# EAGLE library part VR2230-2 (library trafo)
TRANSFORMER 1 primary winding, 2 secondary windings, mounting holes BLOCK

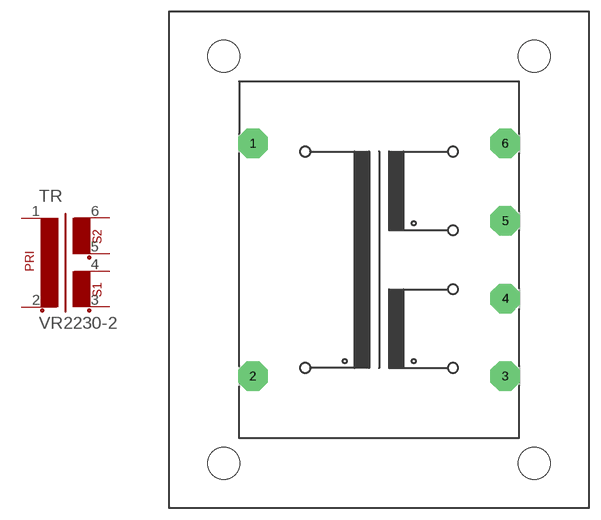
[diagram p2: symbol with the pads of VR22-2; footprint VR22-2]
Designator prefix TR

## VR2230-2  [VR22-2]
1  1  pas
2  2  pas
3  3  pas
4  4  pas
5  5  pas
6  6  pas

## Footprint VR22-2 (pad centres in mm)
TRANSFORMER 1 primary winding, 2 secondary windings, mounting holes
drill 1.397 pad 3.81 octagon: 1 -16.256,15.011; 2 -16.256,-15.011; 3 16.256,-15.011; 4 16.256,-5.004; 5 16.256,5.004; 6 16.256,15.011
hole 4.115 at -19.99,-26.264
hole 4.115 at -19.99,26.264
hole 4.115 at 19.99,-26.264
hole 4.115 at 19.99,26.264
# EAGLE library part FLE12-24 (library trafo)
TRANSFORMER 2 primary winding, temp. protection fuse, 2 secondary windings, mounting holes BLOCK

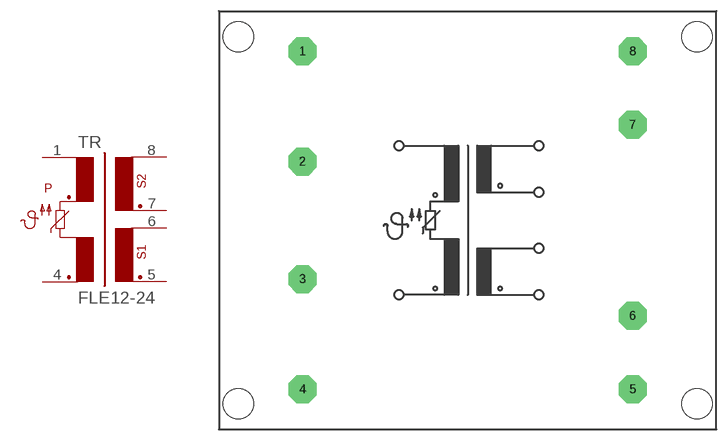
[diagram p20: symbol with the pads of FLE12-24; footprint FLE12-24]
Designator prefix TR

## FLE12-24  [FLE12-24]
1  1  pas
4  4  pas
5  5  pas
6  6  pas
7  7  pas
8  8  pas

## Footprint FLE12-24 (pad centres in mm)
TRANSFORMER 2 primary winding, 2 secondary windings, temp. protection fuse, mounting holes
drill 1.194 pad 3.81 octagon: 1 -22.504,23.012; 2 -22.504,8.001; 3 -22.504,-8.001; 4 -22.504,-23.012; 5 22.504,-23.012; 6 22.504,-13.005; 7 22.504,13.005; 8 22.504,23.012
hole 4.115 at -31.267,24.994
hole 4.115 at 31.267,24.994
hole 4.115 at 31.267,-24.994
hole 4.115 at -31.267,-24.994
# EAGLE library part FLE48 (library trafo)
TRANSFORMER 2 primary winding, temp. protection fuse, 2 secondary windings, mounting holes BLOCK

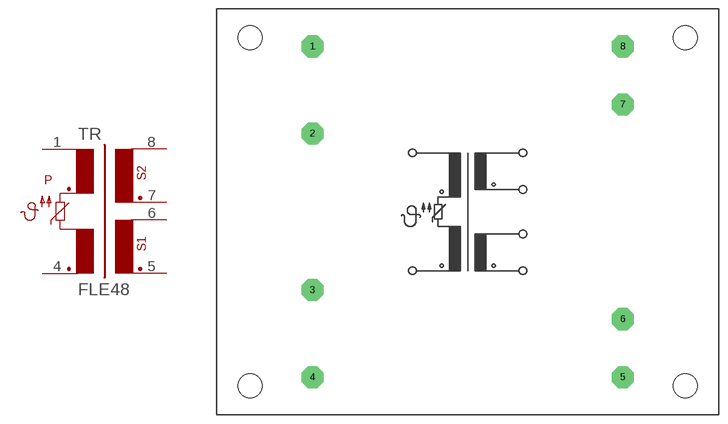
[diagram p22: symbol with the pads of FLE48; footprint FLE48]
Designator prefix TR

## FLE48  [FLE48]
1  1  pas
4  4  pas
5  5  pas
6  6  pas
7  7  pas
8  8  pas

## Footprint FLE48 (pad centres in mm)
TRANSFORMER 2 primary winding, 2 secondary windings, temp. protection fuse, mounting holes
drill 1.397 pad 3.81 octagon: 1 -26.746,28.499; 2 -26.746,13.487; 3 -26.746,-13.487; 4 -26.746,-28.499; 5 26.746,-28.499; 6 26.746,-18.491; 7 26.746,18.491; 8 26.746,28.499
hole 4.115 at -37.49,-29.997
hole 4.115 at -37.49,29.997
hole 4.115 at 37.49,29.997
hole 4.115 at 37.49,-29.997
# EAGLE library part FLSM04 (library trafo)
TRANSFORMER 2 primary winding, temp. protection fuse, 2 secondary windings, smd pads, mounting holes BLOCK

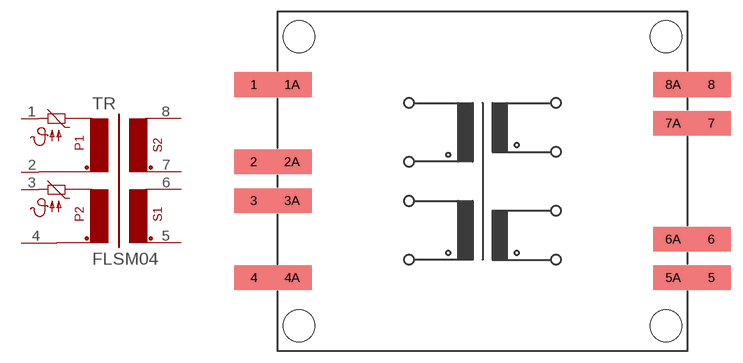
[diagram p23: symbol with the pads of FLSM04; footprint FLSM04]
Designator prefix TR

## FLSM04  [FLSM04]
1  1  pas
2  2  pas
3  3  pas
4  4  pas
5  5  pas
6  6  pas
7  7  pas
8  8  pas

## Footprint FLSM04 (pad centres in mm)
TRANSFORMER 2 primary winding, 2 secondary windings, with smd pads, mounting holes
smd 5.08 x 3.2: 1 -29.616,12.522; 1A -24.663,12.522; 2 -29.616,2.515; 2A -24.663,2.515; 3 -29.616,-2.515; 3A -24.663,-2.515; 4 -29.616,-12.497; 4A -24.663,-12.497; 5 29.616,-12.497; 5A 24.663,-12.497; 6 29.616,-7.518; 6A 24.663,-7.518; 7 29.616,7.518; 7A 24.663,7.518; 8 29.616,12.522; 8A 24.663,12.522
hole 4.115 at 23.749,18.745
hole 4.115 at 23.749,-18.745
hole 4.115 at -23.749,-18.745
hole 4.115 at -23.749,18.745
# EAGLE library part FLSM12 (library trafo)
TRANSFORMER 2 primary winding, temp. protection fuse, 2 secondary windings, smd pads,, mounting holes BLOCK

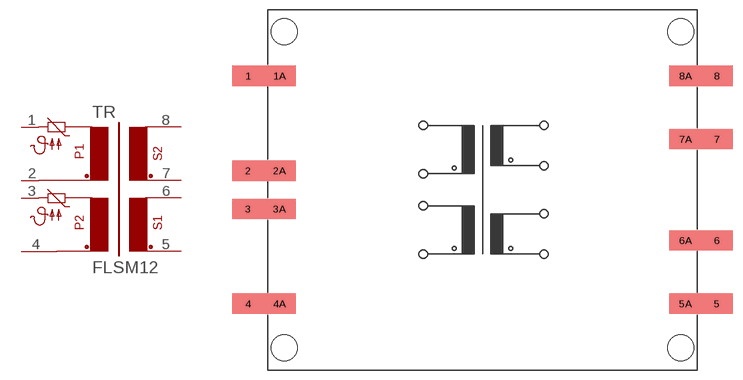
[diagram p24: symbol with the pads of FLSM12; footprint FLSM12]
Designator prefix TR

## FLSM12  [FLSM12]
1  1  pas
2  2  pas
3  3  pas
4  4  pas
5  5  pas
6  6  pas
7  7  pas
8  8  pas

## Footprint FLSM12 (pad centres in mm)
TRANSFORMER 2 primary winding, 2 secondary windings, with smd pads, mounting holes
smd 5.08 x 3.2: 1 -37.008,18.009; 1A -32.055,18.009; 2 -37.008,3.023; 2A -32.055,3.023; 3 -37.008,-3.023; 3A -32.055,-3.023; 4 -37.008,-18.009; 4A -32.055,-18.009; 5 37.008,-18.009; 5A 32.055,-18.009; 6 37.008,-8.001; 6A 32.055,-8.001; 7 37.008,8.001; 7A 32.055,8.001; 8 37.008,18.009; 8A 32.055,18.009
hole 4.115 at -31.267,24.994
hole 4.115 at 31.267,24.994
hole 4.115 at 31.267,-24.994
hole 4.115 at -31.267,-24.994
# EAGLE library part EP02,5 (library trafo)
TRANSFORMER 1 primary winding, 1 secondary winding BLOCK

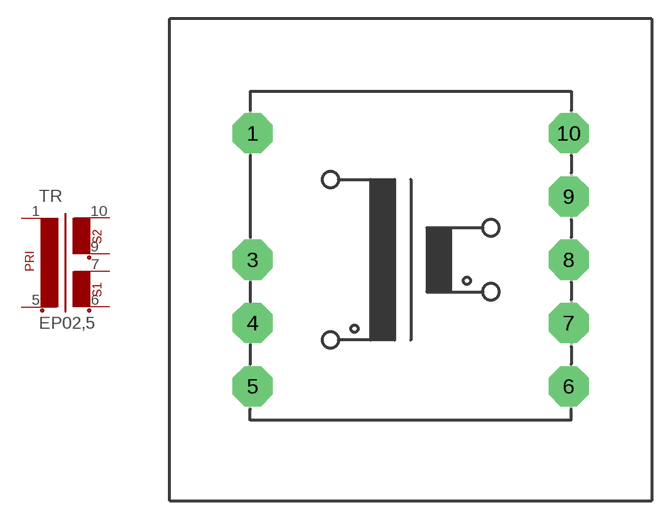
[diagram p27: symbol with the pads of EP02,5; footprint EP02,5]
Designator prefix TR

## EP02,5  [EP02,5]
1  1  pas
5  2  pas
6  3  pas
7  4  pas
9  5  pas
10  6  pas

## Footprint EP02,5 (pad centres in mm)
TRANSFORMER 1 primary winding, 1 secondary winding
drill 1.118 pad 3.175 octagon: 1 -12.497,10.008; 3 -12.497,0; 4 -12.497,-5.004; 5 -12.497,-10.008; 6 12.497,-10.008; 7 12.497,-5.004; 8 12.497,0; 9 12.497,5.004; 10 12.497,10.008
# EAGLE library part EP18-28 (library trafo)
TRANSFORMER 1 primary winding, 2 secondary windings, mounting holes BLOCK

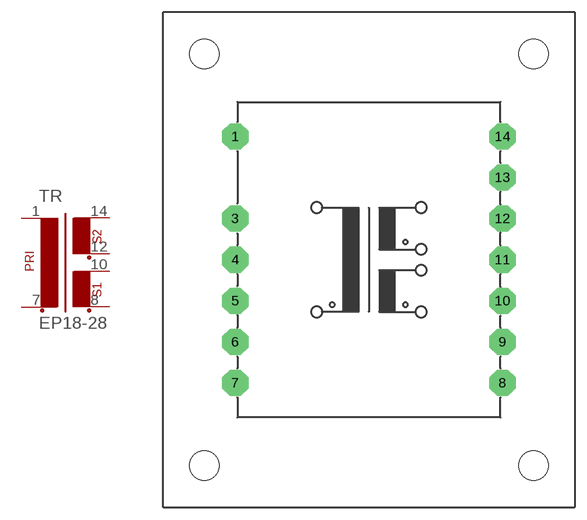
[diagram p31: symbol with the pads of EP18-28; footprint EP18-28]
Designator prefix TR

## EP18-28  [EP18-28]
1  1  pas
7  2  pas
8  3  pas
10  4  pas
12  5  pas
14  6  pas

## Footprint EP18-28 (pad centres in mm)
TRANSFORMER 1 primary winding, 2 secondary windings, mounting holes
drill 1.118 pad 3.175 octagon: 1 -16.256,14.986; 3 -16.256,5.004; 4 -16.256,0; 5 -16.256,-5.004; 6 -16.256,-10.008; 7 -16.256,-14.986; 8 16.256,-14.986; 9 16.256,-10.008; 10 16.256,-5.004; 11 16.256,0; 12 16.256,5.004; 13 16.256,10.008; 14 16.256,14.986
hole 3.607 at -20.015,25.019
hole 3.607 at -20.015,-25.019
hole 3.607 at 20.015,25.019
hole 3.607 at 20.015,-25.019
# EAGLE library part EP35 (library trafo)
TRANSFORMER 1 primary winding, 2 secondary windings, mounting holes BLOCK

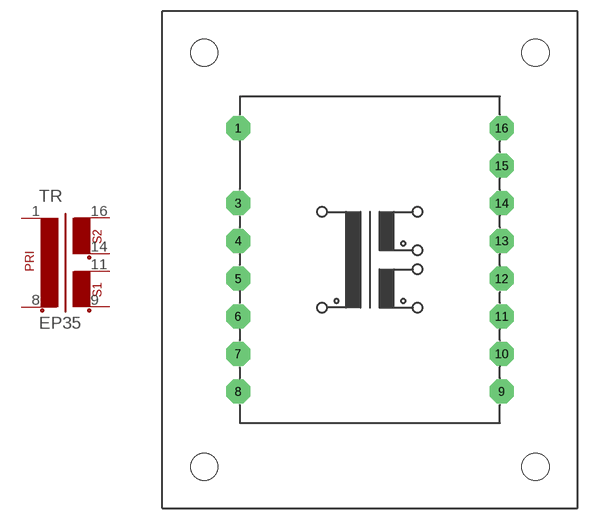
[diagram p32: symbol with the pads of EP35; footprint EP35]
Designator prefix TR

## EP35  [EP35]
1  1  pas
8  2  pas
9  3  pas
11  4  pas
14  5  pas
16  6  pas

## Footprint EP35 (pad centres in mm)
TRANSFORMER 1 primary winding, 2 secondary windings, mounting holes
drill 1.118 pad 3.175 octagon: 1 -17.501,17.501; 3 -17.501,7.518; 4 -17.501,2.515; 5 -17.501,-2.515; 6 -17.501,-7.518; 7 -17.501,-12.497; 8 -17.501,-17.501; 9 17.501,-17.501; 10 17.501,-12.497; 11 17.501,-7.518; 12 17.501,-2.515; 13 17.501,2.515; 14 17.501,7.518; 15 17.501,12.497; 16 17.501,17.501
hole 3.607 at -21.996,27.508
hole 3.607 at -21.996,-27.508
hole 3.607 at 21.996,27.508
hole 3.607 at 21.996,-27.508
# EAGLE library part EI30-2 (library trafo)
TRANSFORMER 1 primary winding, 2 secondary windings ERA

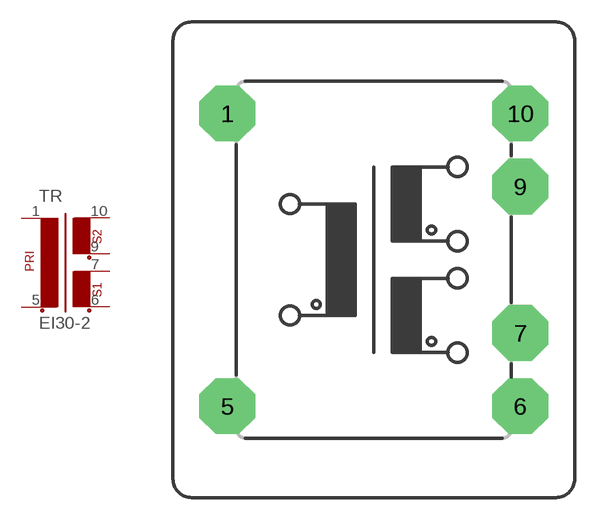
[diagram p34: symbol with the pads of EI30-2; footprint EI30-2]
Designator prefix TR

## EI30-2  [EI30-2]
1  1  pas
5  2  pas
6  3  pas
7  4  pas
9  5  pas
10  6  pas

## Footprint EI30-2 (pad centres in mm)
TRANSFORMER 1 primary winding, 2 secondary windings
drill 1.118 pad 3.81 octagon: 1 -10.008,10.008; 5 -10.008,-10.008; 6 10.008,-10.008; 7 10.008,-5.004; 9 10.008,5.004; 10 10.008,10.008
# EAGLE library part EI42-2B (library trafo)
TRANSFORMER 1 primary winding, 2 secondary windings, mounting holes ERA

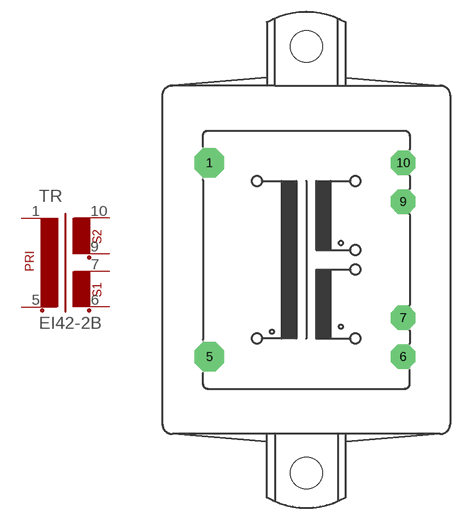
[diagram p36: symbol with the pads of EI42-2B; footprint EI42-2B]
Designator prefix TR

## EI42-2B  [EI42-2B]
1  1  pas
5  2  pas
6  3  pas
7  4  pas
9  5  pas
10  6  pas

## Footprint EI42-2B (pad centres in mm)
TRANSFORMER 1 primary winding, 2 secondary windings, mounting holes
drill 1.118 pad 3.81 octagon: 1 -12.497,12.497; 5 -12.497,-12.497
drill 1.118 pad 3.175 octagon: 6 12.497,-12.497; 7 12.497,-7.493; 9 12.497,7.493; 10 12.497,12.497
hole 4.115 at 0,-27.508
hole 4.115 at 0,27.508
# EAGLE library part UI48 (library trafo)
TRANSFORMER 2 primary winding, 2 secondary windings, mounting holes ERA

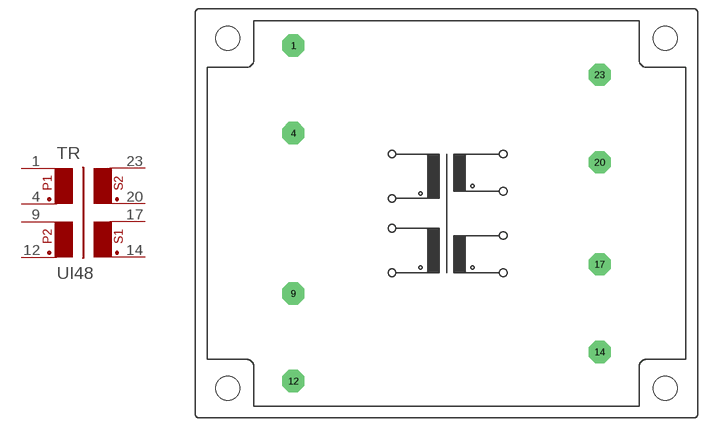
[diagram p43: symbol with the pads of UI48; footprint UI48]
Designator prefix TR

## UI48  [UI48]
1  1  pas
4  2  pas
9  3  pas
12  4  pas
14  5  pas
17  6  pas
20  7  pas
23  8  pas

## Footprint UI48 (pad centres in mm)
TRANSFORMER 2 primary winding, 2 secondary windings, mounting holes
drill 1.194 pad 3.81 octagon: 1 -26.238,28.753; 4 -26.238,13.741; 9 -26.238,-13.741; 12 -26.238,-28.753; 14 26.238,-23.749; 17 26.238,-8.738; 20 26.238,8.738; 23 26.238,23.749
hole 4.115 at 37.49,-29.997
hole 4.115 at -37.49,-29.997
hole 4.115 at -37.49,29.997
hole 4.115 at 37.49,29.997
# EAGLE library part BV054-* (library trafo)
ERA EI 54/18,8 16 VA Source: 207-5567.pdf

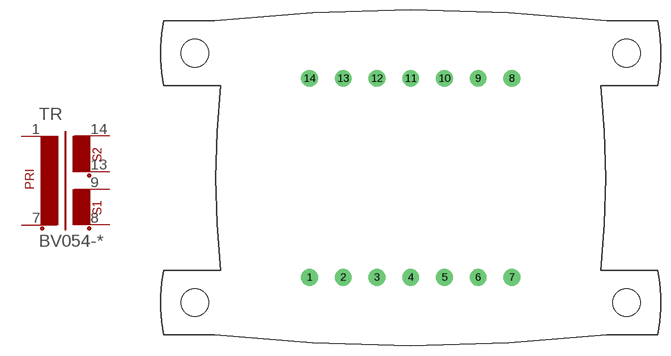
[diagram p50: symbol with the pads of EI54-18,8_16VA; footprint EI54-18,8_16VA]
Designator prefix TR

## BV054-5387.0K, BV054-5388.0K, BV054-5389.0K, BV054-5390.0K  [EI54-18,8_16VA]
1  1  pas
7  2  pas
8  3  pas
9  4  pas
13  5  pas
14  6  pas

## Footprint EI54-18,8_16VA (pad centres in mm)
Type EI 54/18,8 16 VA Source: 207-5567.pdf
drill 1.1 pad 2.54 round: 1 -15.24,-14.986; 2 -10.16,-14.986; 3 -5.08,-14.986; 4 0,-14.986; 5 5.08,-14.986; 6 10.16,-14.986; 7 15.24,-14.986; 8 15.24,14.986; 9 10.16,14.986; 10 5.08,14.986; 11 0,14.986; 12 -5.08,14.986; 13 -10.16,14.986; 14 -15.24,14.986
hole 4.191 at -32.512,-18.796
hole 4.191 at 32.512,-18.796
hole 4.191 at 32.512,18.796
hole 4.191 at -32.512,18.796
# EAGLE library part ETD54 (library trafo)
Economic Transformer Design Source: www.hogenkamp-trafo.de .. ferrit_bauform.pdf

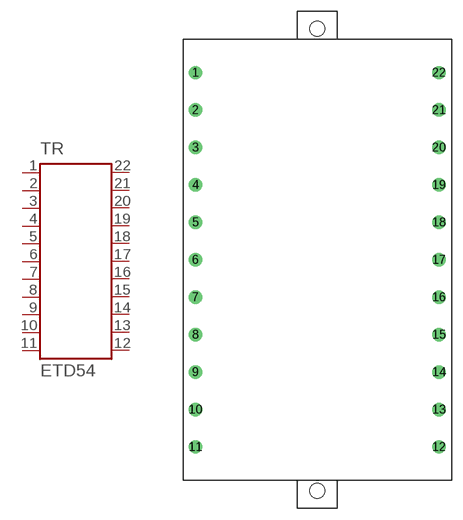
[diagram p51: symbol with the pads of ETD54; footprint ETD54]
Designator prefix TR

## ETD54  [ETD54]
1  1  pas
2  2  pas
3  3  pas
4  4  pas
5  5  pas
6  6  pas
7  7  pas
8  8  pas
9  9  pas
10  10  pas
11  11  pas
12  12  pas
13  13  pas
14  14  pas
15  15  pas
16  16  pas
17  17  pas
18  18  pas
19  19  pas
20  20  pas
21  21  pas
22  22  pas

## Footprint ETD54 (pad centres in mm)
Economic Transformer Design Source: www.hogenkamp-trafo.de .. ferrit_bauform.pdf
drill 1.2 pad 1.778 round: 1 -16.51,25.4; 2 -16.51,20.32; 3 -16.51,15.24; 4 -16.51,10.16; 5 -16.51,5.08; 6 -16.51,0; 7 -16.51,-5.08; 8 -16.51,-10.16; 9 -16.51,-15.24; 10 -16.51,-20.32; 11 -16.51,-25.4; 12 16.51,-25.4; 13 16.51,-20.32; 14 16.51,-15.24; 15 16.51,-10.16; 16 16.51,-5.08; 17 16.51,0; 18 16.51,5.08; 19 16.51,10.16; 20 16.51,15.24; 21 16.51,20.32; 22 16.51,25.4
hole 2 at 0,-31.35
hole 2 at 0,31.35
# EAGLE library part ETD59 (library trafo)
Economic Transformer Design Source: www.hogenkamp-trafo.de .. ferrit_bauform.pdf

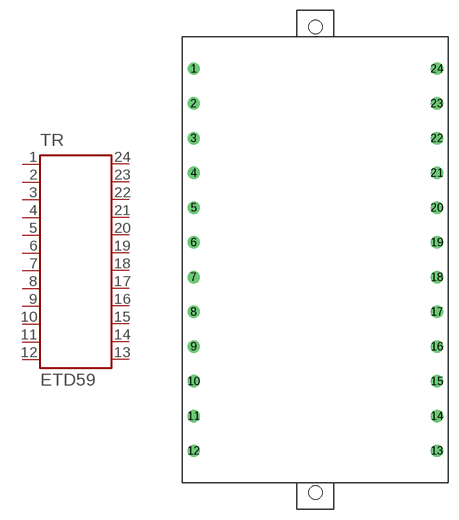
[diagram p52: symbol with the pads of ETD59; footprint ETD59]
Designator prefix TR

## ETD59  [ETD59]
1  1  pas
2  2  pas
3  3  pas
4  4  pas
5  5  pas
6  6  pas
7  7  pas
8  8  pas
9  9  pas
10  10  pas
11  11  pas
12  12  pas
13  13  pas
14  14  pas
15  15  pas
16  16  pas
17  17  pas
18  18  pas
19  19  pas
20  20  pas
21  21  pas
22  22  pas
23  23  pas
24  24  pas

## Footprint ETD59 (pad centres in mm)
drill 1.2 pad 1.778 round: 1 -17.78,27.94; 2 -17.78,22.86; 3 -17.78,17.78; 4 -17.78,12.7; 5 -17.78,7.62; 6 -17.78,2.54; 7 -17.78,-2.54; 8 -17.78,-7.62; 9 -17.78,-12.7; 10 -17.78,-17.78; 11 -17.78,-22.86; 12 -17.78,-27.94; 13 17.78,-27.94; 14 17.78,-22.86; 15 17.78,-17.78; 16 17.78,-12.7; 17 17.78,-7.62; 18 17.78,-2.54; 19 17.78,2.54; 20 17.78,7.62; 21 17.78,12.7; 22 17.78,17.78; 23 17.78,22.86; 24 17.78,27.94
hole 2 at 0,-34.05
hole 2 at 0,34.05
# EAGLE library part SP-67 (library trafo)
Audio Transformer MIL-T-27E High Reliability: Red Spec Series Source: www.triadmagnetics.com .. SP-67.pdf

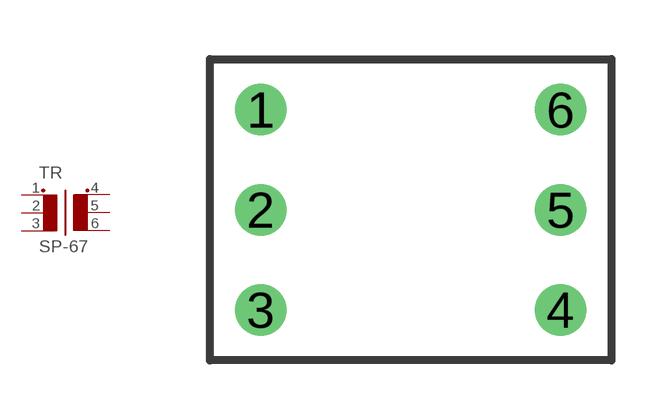
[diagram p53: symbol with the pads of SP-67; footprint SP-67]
Designator prefix TR

## SP-67  [SP-67]
1  1  pas
2  2  pas
3  3  pas
4  4  pas
5  5  pas
6  6  pas

## Footprint SP-67 (pad centres in mm)
Audio Transformer MIL-T-27E High Reliability: Red Spec Series Source: www.triadmagnetics.com .. SP-67.pdf
drill 0.8 round: 1 -3.81,2.54; 2 -3.81,0; 3 -3.81,-2.54; 4 3.81,-2.54; 5 3.81,0; 6 3.81,2.54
